VERSION 5.7 ;
  NOWIREEXTENSIONATPIN ON ;
  DIVIDERCHAR "/" ;
  BUSBITCHARS "[]" ;
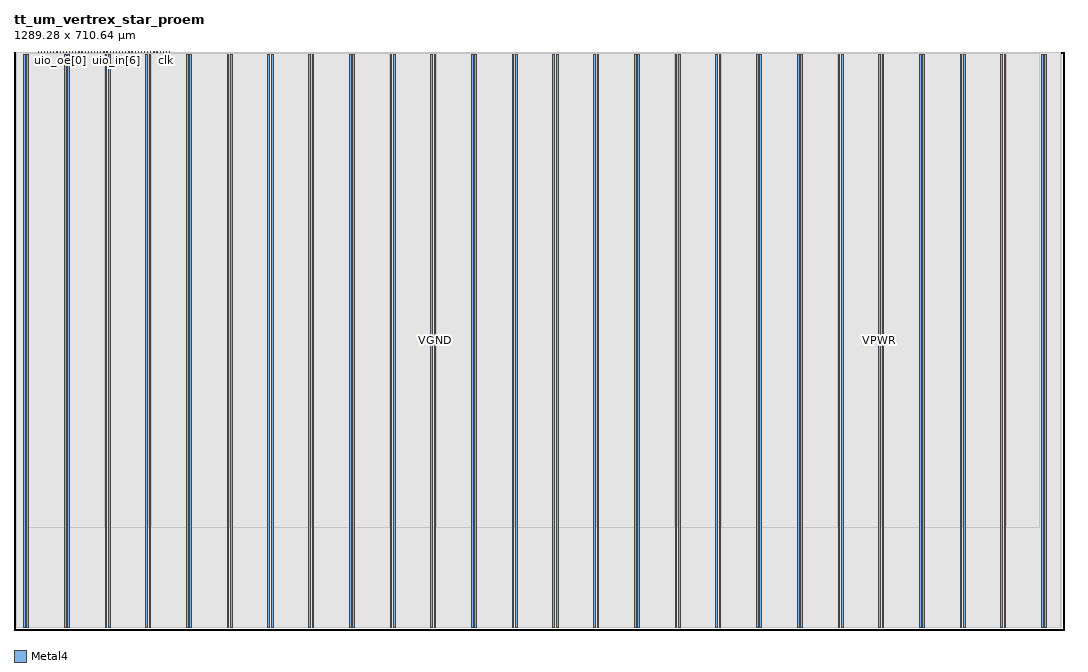
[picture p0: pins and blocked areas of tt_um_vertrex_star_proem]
MACRO tt_um_vertrex_star_proem
  CLASS BLOCK ;
  FOREIGN tt_um_vertrex_star_proem ;
  ORIGIN 0.000 0.000 ;
  SIZE 1289.280 BY 710.640 ;
  PIN VGND
    DIRECTION INOUT ;
    USE GROUND ;
    PORT
      LAYER Metal4 ;
        RECT 15.930 3.560 18.030 707.080 ;
    END
    PORT
      LAYER Metal4 ;
        RECT 65.930 3.560 68.030 707.080 ;
    END
    PORT
      LAYER Metal4 ;
        RECT 115.930 3.560 118.030 707.080 ;
    END
    PORT
      LAYER Metal4 ;
        RECT 165.930 3.560 168.030 707.080 ;
    END
    PORT
      LAYER Metal4 ;
        RECT 215.930 3.560 218.030 707.080 ;
    END
    PORT
      LAYER Metal4 ;
        RECT 265.930 3.560 268.030 707.080 ;
    END
    PORT
      LAYER Metal4 ;
        RECT 315.930 3.560 318.030 707.080 ;
    END
    PORT
      LAYER Metal4 ;
        RECT 365.930 3.560 368.030 707.080 ;
    END
    PORT
      LAYER Metal4 ;
        RECT 415.930 3.560 418.030 707.080 ;
    END
    PORT
      LAYER Metal4 ;
        RECT 465.930 3.560 468.030 707.080 ;
    END
    PORT
      LAYER Metal4 ;
        RECT 515.930 3.560 518.030 707.080 ;
    END
    PORT
      LAYER Metal4 ;
        RECT 565.930 3.560 568.030 707.080 ;
    END
    PORT
      LAYER Metal4 ;
        RECT 615.930 3.560 618.030 707.080 ;
    END
    PORT
      LAYER Metal4 ;
        RECT 665.930 3.560 668.030 707.080 ;
    END
    PORT
      LAYER Metal4 ;
        RECT 715.930 3.560 718.030 707.080 ;
    END
    PORT
      LAYER Metal4 ;
        RECT 765.930 3.560 768.030 707.080 ;
    END
    PORT
      LAYER Metal4 ;
        RECT 815.930 3.560 818.030 707.080 ;
    END
    PORT
      LAYER Metal4 ;
        RECT 865.930 3.560 868.030 707.080 ;
    END
    PORT
      LAYER Metal4 ;
        RECT 915.930 3.560 918.030 707.080 ;
    END
    PORT
      LAYER Metal4 ;
        RECT 965.930 3.560 968.030 707.080 ;
    END
    PORT
      LAYER Metal4 ;
        RECT 1015.930 3.560 1018.030 707.080 ;
    END
    PORT
      LAYER Metal4 ;
        RECT 1065.930 3.560 1068.030 707.080 ;
    END
    PORT
      LAYER Metal4 ;
        RECT 1115.930 3.560 1118.030 707.080 ;
    END
    PORT
      LAYER Metal4 ;
        RECT 1165.930 3.560 1168.030 707.080 ;
    END
    PORT
      LAYER Metal4 ;
        RECT 1215.930 3.560 1218.030 707.080 ;
    END
    PORT
      LAYER Metal4 ;
        RECT 1265.930 3.560 1268.030 707.080 ;
    END
  END VGND
  PIN VPWR
    DIRECTION INOUT ;
    USE POWER ;
    PORT
      LAYER Metal4 ;
        RECT 11.830 3.560 13.930 707.080 ;
    END
    PORT
      LAYER Metal4 ;
        RECT 61.830 3.560 63.930 707.080 ;
    END
    PORT
      LAYER Metal4 ;
        RECT 111.830 3.560 113.930 707.080 ;
    END
    PORT
      LAYER Metal4 ;
        RECT 161.830 3.560 163.930 707.080 ;
    END
    PORT
      LAYER Metal4 ;
        RECT 211.830 3.560 213.930 707.080 ;
    END
    PORT
      LAYER Metal4 ;
        RECT 261.830 3.560 263.930 707.080 ;
    END
    PORT
      LAYER Metal4 ;
        RECT 311.830 3.560 313.930 707.080 ;
    END
    PORT
      LAYER Metal4 ;
        RECT 361.830 3.560 363.930 707.080 ;
    END
    PORT
      LAYER Metal4 ;
        RECT 411.830 3.560 413.930 707.080 ;
    END
    PORT
      LAYER Metal4 ;
        RECT 461.830 3.560 463.930 707.080 ;
    END
    PORT
      LAYER Metal4 ;
        RECT 511.830 3.560 513.930 707.080 ;
    END
    PORT
      LAYER Metal4 ;
        RECT 561.830 3.560 563.930 707.080 ;
    END
    PORT
      LAYER Metal4 ;
        RECT 611.830 3.560 613.930 707.080 ;
    END
    PORT
      LAYER Metal4 ;
        RECT 661.830 3.560 663.930 707.080 ;
    END
    PORT
      LAYER Metal4 ;
        RECT 711.830 3.560 713.930 707.080 ;
    END
    PORT
      LAYER Metal4 ;
        RECT 761.830 3.560 763.930 707.080 ;
    END
    PORT
      LAYER Metal4 ;
        RECT 811.830 3.560 813.930 707.080 ;
    END
    PORT
      LAYER Metal4 ;
        RECT 861.830 3.560 863.930 707.080 ;
    END
    PORT
      LAYER Metal4 ;
        RECT 911.830 3.560 913.930 707.080 ;
    END
    PORT
      LAYER Metal4 ;
        RECT 961.830 3.560 963.930 707.080 ;
    END
    PORT
      LAYER Metal4 ;
        RECT 1011.830 3.560 1013.930 707.080 ;
    END
    PORT
      LAYER Metal4 ;
        RECT 1061.830 3.560 1063.930 707.080 ;
    END
    PORT
      LAYER Metal4 ;
        RECT 1111.830 3.560 1113.930 707.080 ;
    END
    PORT
      LAYER Metal4 ;
        RECT 1161.830 3.560 1163.930 707.080 ;
    END
    PORT
      LAYER Metal4 ;
        RECT 1211.830 3.560 1213.930 707.080 ;
    END
    PORT
      LAYER Metal4 ;
        RECT 1261.830 3.560 1263.930 707.080 ;
    END
  END VPWR
  PIN clk
    DIRECTION INPUT ;
    USE SIGNAL ;
    ANTENNAGATEAREA 0.725400 ;
    ANTENNADIFFAREA 2.015400 ;
    PORT
      LAYER Metal4 ;
        RECT 187.050 709.640 187.350 710.640 ;
    END
  END clk
  PIN ena
    DIRECTION INPUT ;
    USE SIGNAL ;
    PORT
      LAYER Metal4 ;
        RECT 190.890 709.640 191.190 710.640 ;
    END
  END ena
  PIN rst_n
    DIRECTION INPUT ;
    USE SIGNAL ;
    ANTENNAGATEAREA 0.180700 ;
    PORT
      LAYER Metal4 ;
        RECT 183.210 709.640 183.510 710.640 ;
    END
  END rst_n
  PIN ui_in[0]
    DIRECTION INPUT ;
    USE SIGNAL ;
    ANTENNAGATEAREA 0.180700 ;
    PORT
      LAYER Metal4 ;
        RECT 179.370 709.640 179.670 710.640 ;
    END
  END ui_in[0]
  PIN ui_in[1]
    DIRECTION INPUT ;
    USE SIGNAL ;
    PORT
      LAYER Metal4 ;
        RECT 175.530 709.640 175.830 710.640 ;
    END
  END ui_in[1]
  PIN ui_in[2]
    DIRECTION INPUT ;
    USE SIGNAL ;
    PORT
      LAYER Metal4 ;
        RECT 171.690 709.640 171.990 710.640 ;
    END
  END ui_in[2]
  PIN ui_in[3]
    DIRECTION INPUT ;
    USE SIGNAL ;
    PORT
      LAYER Metal4 ;
        RECT 167.850 709.640 168.150 710.640 ;
    END
  END ui_in[3]
  PIN ui_in[4]
    DIRECTION INPUT ;
    USE SIGNAL ;
    PORT
      LAYER Metal4 ;
        RECT 164.010 709.640 164.310 710.640 ;
    END
  END ui_in[4]
  PIN ui_in[5]
    DIRECTION INPUT ;
    USE SIGNAL ;
    PORT
      LAYER Metal4 ;
        RECT 160.170 709.640 160.470 710.640 ;
    END
  END ui_in[5]
  PIN ui_in[6]
    DIRECTION INPUT ;
    USE SIGNAL ;
    PORT
      LAYER Metal4 ;
        RECT 156.330 709.640 156.630 710.640 ;
    END
  END ui_in[6]
  PIN ui_in[7]
    DIRECTION INPUT ;
    USE SIGNAL ;
    PORT
      LAYER Metal4 ;
        RECT 152.490 709.640 152.790 710.640 ;
    END
  END ui_in[7]
  PIN uio_in[0]
    DIRECTION INPUT ;
    USE SIGNAL ;
    ANTENNAGATEAREA 0.180700 ;
    PORT
      LAYER Metal4 ;
        RECT 148.650 709.640 148.950 710.640 ;
    END
  END uio_in[0]
  PIN uio_in[1]
    DIRECTION INPUT ;
    USE SIGNAL ;
    ANTENNAGATEAREA 0.180700 ;
    PORT
      LAYER Metal4 ;
        RECT 144.810 709.640 145.110 710.640 ;
    END
  END uio_in[1]
  PIN uio_in[2]
    DIRECTION INPUT ;
    USE SIGNAL ;
    ANTENNAGATEAREA 0.180700 ;
    PORT
      LAYER Metal4 ;
        RECT 140.970 709.640 141.270 710.640 ;
    END
  END uio_in[2]
  PIN uio_in[3]
    DIRECTION INPUT ;
    USE SIGNAL ;
    ANTENNAGATEAREA 0.180700 ;
    PORT
      LAYER Metal4 ;
        RECT 137.130 709.640 137.430 710.640 ;
    END
  END uio_in[3]
  PIN uio_in[4]
    DIRECTION INPUT ;
    USE SIGNAL ;
    ANTENNAGATEAREA 0.180700 ;
    PORT
      LAYER Metal4 ;
        RECT 133.290 709.640 133.590 710.640 ;
    END
  END uio_in[4]
  PIN uio_in[5]
    DIRECTION INPUT ;
    USE SIGNAL ;
    ANTENNAGATEAREA 0.180700 ;
    PORT
      LAYER Metal4 ;
        RECT 129.450 709.640 129.750 710.640 ;
    END
  END uio_in[5]
  PIN uio_in[6]
    DIRECTION INPUT ;
    USE SIGNAL ;
    ANTENNAGATEAREA 0.180700 ;
    PORT
      LAYER Metal4 ;
        RECT 125.610 709.640 125.910 710.640 ;
    END
  END uio_in[6]
  PIN uio_in[7]
    DIRECTION INPUT ;
    USE SIGNAL ;
    ANTENNAGATEAREA 0.180700 ;
    PORT
      LAYER Metal4 ;
        RECT 121.770 709.640 122.070 710.640 ;
    END
  END uio_in[7]
  PIN uio_oe[0]
    DIRECTION OUTPUT ;
    USE SIGNAL ;
    ANTENNADIFFAREA 0.708600 ;
    PORT
      LAYER Metal4 ;
        RECT 56.490 709.640 56.790 710.640 ;
    END
  END uio_oe[0]
  PIN uio_oe[1]
    DIRECTION OUTPUT ;
    USE SIGNAL ;
    ANTENNADIFFAREA 0.708600 ;
    PORT
      LAYER Metal4 ;
        RECT 52.650 709.640 52.950 710.640 ;
    END
  END uio_oe[1]
  PIN uio_oe[2]
    DIRECTION OUTPUT ;
    USE SIGNAL ;
    ANTENNADIFFAREA 0.708600 ;
    PORT
      LAYER Metal4 ;
        RECT 48.810 709.640 49.110 710.640 ;
    END
  END uio_oe[2]
  PIN uio_oe[3]
    DIRECTION OUTPUT ;
    USE SIGNAL ;
    ANTENNADIFFAREA 0.708600 ;
    PORT
      LAYER Metal4 ;
        RECT 44.970 709.640 45.270 710.640 ;
    END
  END uio_oe[3]
  PIN uio_oe[4]
    DIRECTION OUTPUT ;
    USE SIGNAL ;
    ANTENNADIFFAREA 0.708600 ;
    PORT
      LAYER Metal4 ;
        RECT 41.130 709.640 41.430 710.640 ;
    END
  END uio_oe[4]
  PIN uio_oe[5]
    DIRECTION OUTPUT ;
    USE SIGNAL ;
    ANTENNADIFFAREA 0.708600 ;
    PORT
      LAYER Metal4 ;
        RECT 37.290 709.640 37.590 710.640 ;
    END
  END uio_oe[5]
  PIN uio_oe[6]
    DIRECTION OUTPUT ;
    USE SIGNAL ;
    ANTENNADIFFAREA 0.299200 ;
    PORT
      LAYER Metal4 ;
        RECT 33.450 709.640 33.750 710.640 ;
    END
  END uio_oe[6]
  PIN uio_oe[7]
    DIRECTION OUTPUT ;
    USE SIGNAL ;
    ANTENNADIFFAREA 0.299200 ;
    PORT
      LAYER Metal4 ;
        RECT 29.610 709.640 29.910 710.640 ;
    END
  END uio_oe[7]
  PIN uio_out[0]
    DIRECTION OUTPUT ;
    USE SIGNAL ;
    ANTENNADIFFAREA 0.708600 ;
    PORT
      LAYER Metal4 ;
        RECT 87.210 709.640 87.510 710.640 ;
    END
  END uio_out[0]
  PIN uio_out[1]
    DIRECTION OUTPUT ;
    USE SIGNAL ;
    ANTENNADIFFAREA 0.708600 ;
    PORT
      LAYER Metal4 ;
        RECT 83.370 709.640 83.670 710.640 ;
    END
  END uio_out[1]
  PIN uio_out[2]
    DIRECTION OUTPUT ;
    USE SIGNAL ;
    ANTENNADIFFAREA 0.708600 ;
    PORT
      LAYER Metal4 ;
        RECT 79.530 709.640 79.830 710.640 ;
    END
  END uio_out[2]
  PIN uio_out[3]
    DIRECTION OUTPUT ;
    USE SIGNAL ;
    ANTENNADIFFAREA 0.708600 ;
    PORT
      LAYER Metal4 ;
        RECT 75.690 709.640 75.990 710.640 ;
    END
  END uio_out[3]
  PIN uio_out[4]
    DIRECTION OUTPUT ;
    USE SIGNAL ;
    ANTENNADIFFAREA 0.708600 ;
    PORT
      LAYER Metal4 ;
        RECT 71.850 709.640 72.150 710.640 ;
    END
  END uio_out[4]
  PIN uio_out[5]
    DIRECTION OUTPUT ;
    USE SIGNAL ;
    ANTENNADIFFAREA 0.708600 ;
    PORT
      LAYER Metal4 ;
        RECT 68.010 709.640 68.310 710.640 ;
    END
  END uio_out[5]
  PIN uio_out[6]
    DIRECTION OUTPUT ;
    USE SIGNAL ;
    ANTENNADIFFAREA 0.299200 ;
    PORT
      LAYER Metal4 ;
        RECT 64.170 709.640 64.470 710.640 ;
    END
  END uio_out[6]
  PIN uio_out[7]
    DIRECTION OUTPUT ;
    USE SIGNAL ;
    ANTENNADIFFAREA 0.299200 ;
    PORT
      LAYER Metal4 ;
        RECT 60.330 709.640 60.630 710.640 ;
    END
  END uio_out[7]
  PIN uo_out[0]
    DIRECTION OUTPUT ;
    USE SIGNAL ;
    ANTENNADIFFAREA 0.708600 ;
    PORT
      LAYER Metal4 ;
        RECT 117.930 709.640 118.230 710.640 ;
    END
  END uo_out[0]
  PIN uo_out[1]
    DIRECTION OUTPUT ;
    USE SIGNAL ;
    ANTENNADIFFAREA 0.708600 ;
    PORT
      LAYER Metal4 ;
        RECT 114.090 709.640 114.390 710.640 ;
    END
  END uo_out[1]
  PIN uo_out[2]
    DIRECTION OUTPUT ;
    USE SIGNAL ;
    ANTENNADIFFAREA 0.708600 ;
    PORT
      LAYER Metal4 ;
        RECT 110.250 709.640 110.550 710.640 ;
    END
  END uo_out[2]
  PIN uo_out[3]
    DIRECTION OUTPUT ;
    USE SIGNAL ;
    ANTENNADIFFAREA 0.708600 ;
    PORT
      LAYER Metal4 ;
        RECT 106.410 709.640 106.710 710.640 ;
    END
  END uo_out[3]
  PIN uo_out[4]
    DIRECTION OUTPUT ;
    USE SIGNAL ;
    ANTENNADIFFAREA 0.708600 ;
    PORT
      LAYER Metal4 ;
        RECT 102.570 709.640 102.870 710.640 ;
    END
  END uo_out[4]
  PIN uo_out[5]
    DIRECTION OUTPUT ;
    USE SIGNAL ;
    ANTENNADIFFAREA 0.708600 ;
    PORT
      LAYER Metal4 ;
        RECT 98.730 709.640 99.030 710.640 ;
    END
  END uo_out[5]
  PIN uo_out[6]
    DIRECTION OUTPUT ;
    USE SIGNAL ;
    ANTENNADIFFAREA 0.708600 ;
    PORT
      LAYER Metal4 ;
        RECT 94.890 709.640 95.190 710.640 ;
    END
  END uo_out[6]
  PIN uo_out[7]
    DIRECTION OUTPUT ;
    USE SIGNAL ;
    ANTENNADIFFAREA 0.708600 ;
    PORT
      LAYER Metal4 ;
        RECT 91.050 709.640 91.350 710.640 ;
    END
  END uo_out[7]
  OBS
      LAYER GatPoly ;
        RECT 2.880 3.630 1286.400 707.010 ;
      LAYER Metal1 ;
        RECT 2.880 3.560 1286.400 707.080 ;
      LAYER Metal2 ;
        RECT 2.775 3.635 1284.585 708.685 ;
      LAYER Metal3 ;
        RECT 2.735 3.680 1284.625 708.645 ;
      LAYER Metal4 ;
        RECT 14.300 709.430 29.400 709.640 ;
        RECT 30.120 709.430 33.240 709.640 ;
        RECT 33.960 709.430 37.080 709.640 ;
        RECT 37.800 709.430 40.920 709.640 ;
        RECT 41.640 709.430 44.760 709.640 ;
        RECT 45.480 709.430 48.600 709.640 ;
        RECT 49.320 709.430 52.440 709.640 ;
        RECT 53.160 709.430 56.280 709.640 ;
        RECT 57.000 709.430 60.120 709.640 ;
        RECT 60.840 709.430 63.960 709.640 ;
        RECT 64.680 709.430 67.800 709.640 ;
        RECT 68.520 709.430 71.640 709.640 ;
        RECT 72.360 709.430 75.480 709.640 ;
        RECT 76.200 709.430 79.320 709.640 ;
        RECT 80.040 709.430 83.160 709.640 ;
        RECT 83.880 709.430 87.000 709.640 ;
        RECT 87.720 709.430 90.840 709.640 ;
        RECT 91.560 709.430 94.680 709.640 ;
        RECT 95.400 709.430 98.520 709.640 ;
        RECT 99.240 709.430 102.360 709.640 ;
        RECT 103.080 709.430 106.200 709.640 ;
        RECT 106.920 709.430 110.040 709.640 ;
        RECT 110.760 709.430 113.880 709.640 ;
        RECT 114.600 709.430 117.720 709.640 ;
        RECT 118.440 709.430 121.560 709.640 ;
        RECT 122.280 709.430 125.400 709.640 ;
        RECT 126.120 709.430 129.240 709.640 ;
        RECT 129.960 709.430 133.080 709.640 ;
        RECT 133.800 709.430 136.920 709.640 ;
        RECT 137.640 709.430 140.760 709.640 ;
        RECT 141.480 709.430 144.600 709.640 ;
        RECT 145.320 709.430 148.440 709.640 ;
        RECT 149.160 709.430 152.280 709.640 ;
        RECT 153.000 709.430 156.120 709.640 ;
        RECT 156.840 709.430 159.960 709.640 ;
        RECT 160.680 709.430 163.800 709.640 ;
        RECT 164.520 709.430 167.640 709.640 ;
        RECT 168.360 709.430 171.480 709.640 ;
        RECT 172.200 709.430 175.320 709.640 ;
        RECT 176.040 709.430 179.160 709.640 ;
        RECT 179.880 709.430 183.000 709.640 ;
        RECT 183.720 709.430 186.840 709.640 ;
        RECT 187.560 709.430 190.680 709.640 ;
        RECT 191.400 709.430 1259.140 709.640 ;
        RECT 14.300 707.290 1259.140 709.430 ;
        RECT 14.300 125.435 15.720 707.290 ;
        RECT 18.240 125.435 61.620 707.290 ;
        RECT 64.140 125.435 65.720 707.290 ;
        RECT 68.240 125.435 111.620 707.290 ;
        RECT 114.140 125.435 115.720 707.290 ;
        RECT 118.240 125.435 161.620 707.290 ;
        RECT 164.140 125.435 165.720 707.290 ;
        RECT 168.240 125.435 211.620 707.290 ;
        RECT 214.140 125.435 215.720 707.290 ;
        RECT 218.240 125.435 261.620 707.290 ;
        RECT 264.140 125.435 265.720 707.290 ;
        RECT 268.240 125.435 311.620 707.290 ;
        RECT 314.140 125.435 315.720 707.290 ;
        RECT 318.240 125.435 361.620 707.290 ;
        RECT 364.140 125.435 365.720 707.290 ;
        RECT 368.240 125.435 411.620 707.290 ;
        RECT 414.140 125.435 415.720 707.290 ;
        RECT 418.240 125.435 461.620 707.290 ;
        RECT 464.140 125.435 465.720 707.290 ;
        RECT 468.240 125.435 511.620 707.290 ;
        RECT 514.140 125.435 515.720 707.290 ;
        RECT 518.240 125.435 561.620 707.290 ;
        RECT 564.140 125.435 565.720 707.290 ;
        RECT 568.240 125.435 611.620 707.290 ;
        RECT 614.140 125.435 615.720 707.290 ;
        RECT 618.240 125.435 661.620 707.290 ;
        RECT 664.140 125.435 665.720 707.290 ;
        RECT 668.240 125.435 711.620 707.290 ;
        RECT 714.140 125.435 715.720 707.290 ;
        RECT 718.240 125.435 761.620 707.290 ;
        RECT 764.140 125.435 765.720 707.290 ;
        RECT 768.240 125.435 811.620 707.290 ;
        RECT 814.140 125.435 815.720 707.290 ;
        RECT 818.240 125.435 861.620 707.290 ;
        RECT 864.140 125.435 865.720 707.290 ;
        RECT 868.240 125.435 911.620 707.290 ;
        RECT 914.140 125.435 915.720 707.290 ;
        RECT 918.240 125.435 961.620 707.290 ;
        RECT 964.140 125.435 965.720 707.290 ;
        RECT 968.240 125.435 1011.620 707.290 ;
        RECT 1014.140 125.435 1015.720 707.290 ;
        RECT 1018.240 125.435 1061.620 707.290 ;
        RECT 1064.140 125.435 1065.720 707.290 ;
        RECT 1068.240 125.435 1111.620 707.290 ;
        RECT 1114.140 125.435 1115.720 707.290 ;
        RECT 1118.240 125.435 1161.620 707.290 ;
        RECT 1164.140 125.435 1165.720 707.290 ;
        RECT 1168.240 125.435 1211.620 707.290 ;
        RECT 1214.140 125.435 1215.720 707.290 ;
        RECT 1218.240 125.435 1259.140 707.290 ;
  END
END tt_um_vertrex_star_proem
END LIBRARY

